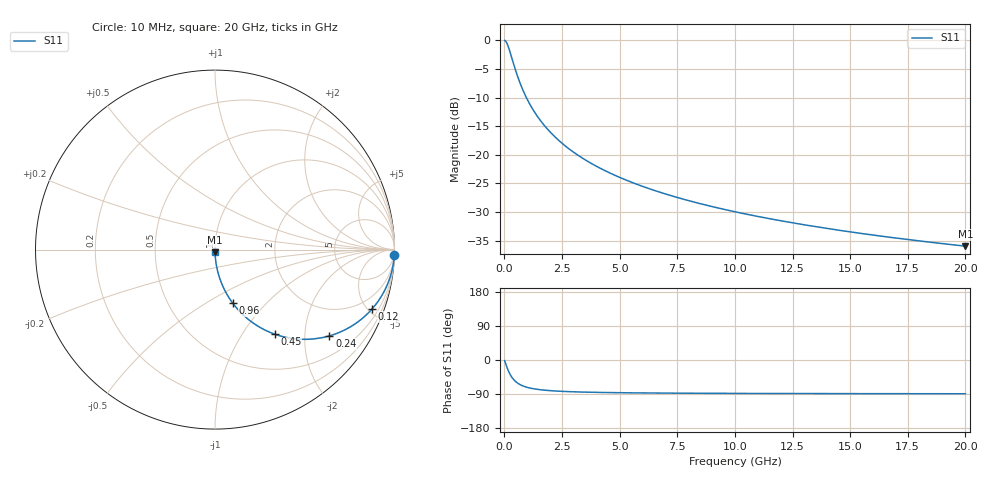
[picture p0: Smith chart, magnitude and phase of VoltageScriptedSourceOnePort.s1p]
! File created by SignalIntegrity v1.5.4: Signal and Power Integrity Tools
! https://github.com/Nubis-Communications/SignalIntegrity
# MHz S MA R 50.0
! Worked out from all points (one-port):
!   2000 points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, 10 MHz to 20 GHz, reference 50 ohm
!   lowest |S11| = -36.0 dB at 20 GHz (marker M1), VSWR 1.03, Z = 50 - j1.59 ohm
!   |S11| at or under -10 dB: 954.9 MHz to end of sweep
!   S11 on the Smith chart (normalised r, x): 10 MHz: 1, -64; 120 MHz: 1.00, -5.31; 240 MHz: 1.00, -2.65; 450 MHz: 1.00, -1.41; 960 MHz: 1.00, -0.66; 20 GHz: 1.00, -0.03
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10  0.9995 -1.8
70  0.9767 -12.4
120  0.9357 -20.7
180  0.8705 -29.5
240  0.7985 -37.0
280  0.7508 -41.3
330  0.6942 -46.0
390  0.6323 -50.8
450  0.5775 -54.7
550  0.5009 -59.9
660  0.4344 -64.3
800  0.3697 -68.3
960  0.3147 -71.7
1270  0.2431 -75.9
1630  0.1917 -79.0
2040  0.1542 -81.1
2510  0.1258 -82.8
3030  0.1045 -84.0
3620  0.08759 -85.0
4280  0.07417 -85.7
5010  0.06341 -86.4
6180  0.05144 -87.1
7510  0.04235 -87.6
10010  0.03178 -88.2
12510  0.02544 -88.5
15010  0.0212 -88.8
17510  0.01818 -89.0
20000  0.01591 -89.1
